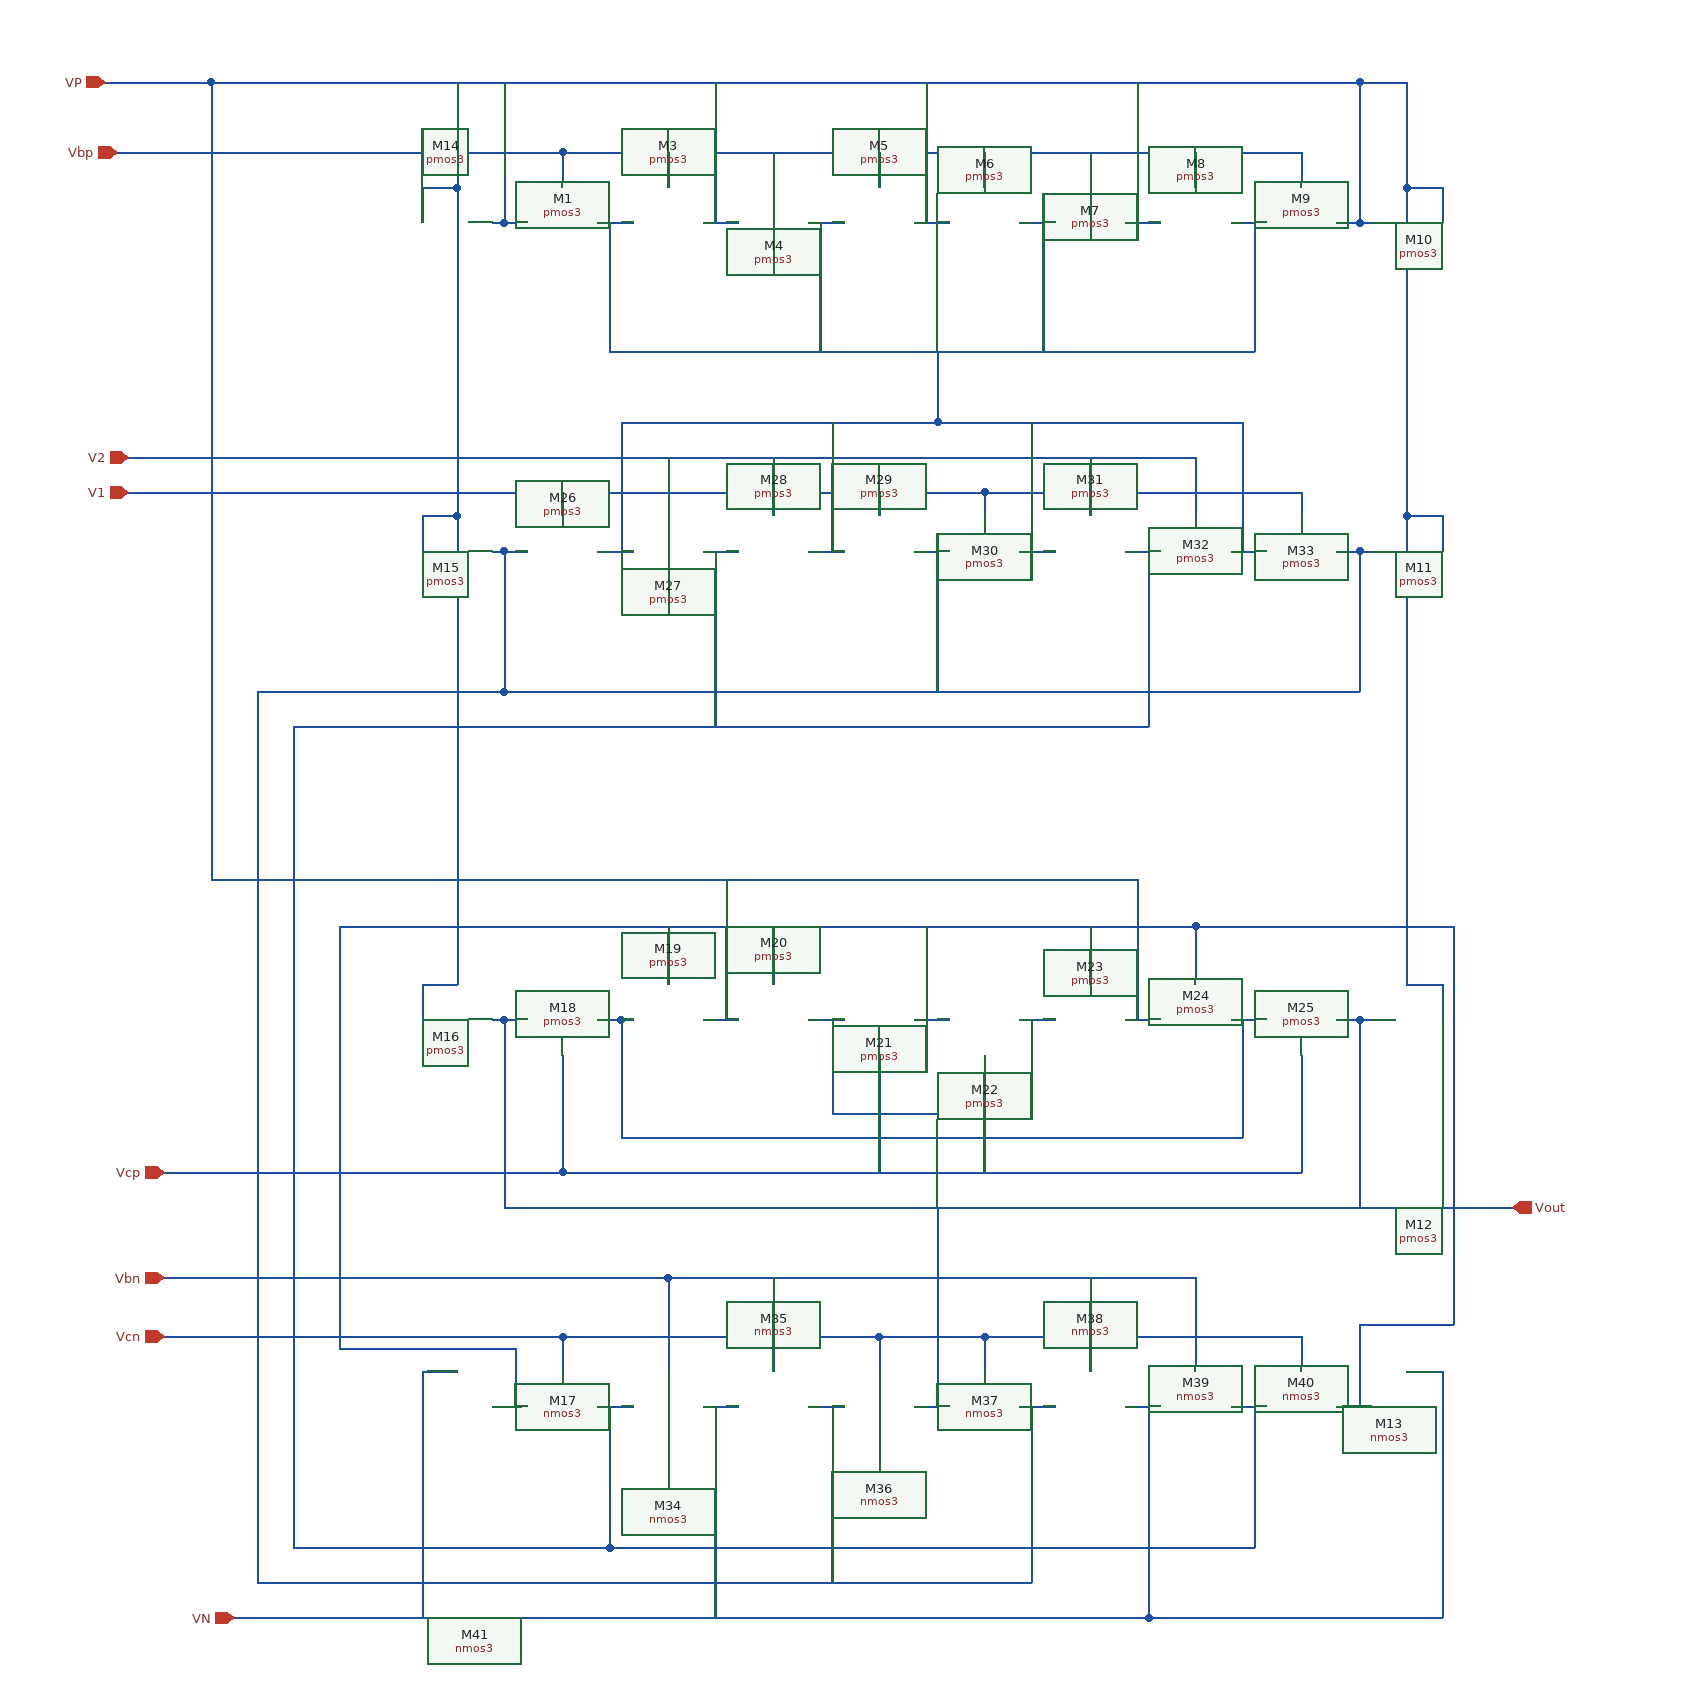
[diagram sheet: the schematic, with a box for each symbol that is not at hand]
v {xschem version=2.9.9 file_version=1.2 }
G {}
K {}
V {}
S {}
E {}
N 510 -1360 510 -1330 { lab=Vbp}
N 510 -1360 1140 -1360 { lab=Vbp}
N 1140 -1360 1140 -1330 { lab=Vbp}
N 1050 -1360 1050 -1330 { lab=Vbp}
N 960 -1360 960 -1330 { lab=Vbp}
N 870 -1360 870 -1330 { lab=Vbp}
N 780 -1360 780 -1330 { lab=Vbp}
N 690 -1360 690 -1330 { lab=Vbp}
N 600 -1360 600 -1330 { lab=Vbp}
N 540 -1300 570 -1300 { lab=#net1}
N 630 -1300 660 -1300 { lab=VP}
N 720 -1300 750 -1300 { lab=#net1}
N 810 -1300 840 -1300 { lab=VP}
N 900 -1300 930 -1300 { lab=#net1}
N 990 -1300 1020 -1300 { lab=VP}
N 1080 -1300 1110 -1300 { lab=#net1}
N 460 -1420 460 -1300 { lab=VP}
N 450 -1420 1190 -1420 { lab=VP}
N 1190 -1420 1190 -1300 { lab=VP}
N 1170 -1300 1190 -1300 { lab=VP}
N 820 -1420 820 -1300 { lab=VP}
N 1000 -1420 1000 -1300 { lab=VP}
N 640 -1420 640 -1300 { lab=VP}
N 350 -1420 450 -1420 { lab=VP}
N 350 -1360 510 -1360 { lab=Vbp}
N 550 -1300 550 -1190 { lab=#net1}
N 550 -1190 1100 -1190 { lab=#net1}
N 1100 -1300 1100 -1190 { lab=#net1}
N 920 -1300 920 -1190 { lab=#net1}
N 730 -1300 730 -1190 { lab=#net1}
N 810 -1020 840 -1020 { lab=#net2}
N 540 -1020 570 -1020 { lab=#net1}
N 630 -1020 660 -1020 { lab=#net3}
N 730 -1020 750 -1020 { lab=#net1}
N 720 -1020 730 -1020 { lab=#net1}
N 900 -1020 930 -1020 { lab=#net1}
N 990 -1020 1020 -1020 { lab=#net3}
N 1080 -1020 1110 -1020 { lab=#net1}
N 780 -1070 780 -1050 { lab=V1}
N 870 -1070 870 -1050 { lab=V1}
N 1140 -1070 1140 -1060 { lab=V1}
N 1140 -1060 1140 -1050 { lab=V1}
N 500 -1070 870 -1070 { lab=V1}
N 510 -1070 510 -1050 { lab=V1}
N 330 -1070 500 -1070 { lab=V1}
N 1050 -1100 1050 -1050 { lab=V2}
N 870 -1070 1140 -1070 { lab=V1}
N 960 -1100 960 -1050 { lab=V2}
N 690 -1090 690 -1050 { lab=V2}
N 600 -1090 600 -1050 { lab=V2}
N 600 -1100 600 -1090 { lab=V2}
N 690 -1100 690 -1090 { lab=V2}
N 330 -1100 1050 -1100 { lab=V2}
N 830 -1190 830 -1150 { lab=#net1}
N 830 -1150 830 -1130 { lab=#net1}
N 560 -1130 830 -1130 { lab=#net1}
N 560 -1130 560 -1020 { lab=#net1}
N 830 -1130 1080 -1130 { lab=#net1}
N 1080 -1130 1090 -1130 { lab=#net1}
N 1090 -1130 1090 -1020 { lab=#net1}
N 740 -1130 740 -1020 { lab=#net1}
N 910 -1130 910 -1020 { lab=#net1}
N 460 -1020 480 -1020 { lab=#net2}
N 460 -1020 460 -900 { lab=#net2}
N 1170 -1020 1190 -1020 { lab=#net2}
N 1190 -1020 1190 -900 { lab=#net2}
N 460 -900 1190 -900 { lab=#net2}
N 830 -1020 830 -900 { lab=#net2}
N 640 -1020 640 -870 { lab=#net3}
N 1010 -1020 1010 -870 { lab=#net3}
N 410 -870 1010 -870 { lab=#net3}
N 380 -900 460 -900 { lab=#net2}
N 810 -620 840 -620 { lab=#net4}
N 720 -620 750 -620 { lab=#net5}
N 900 -620 930 -620 { lab=#net5}
N 990 -620 1020 -620 { lab=VP}
N 630 -620 660 -620 { lab=VP}
N 1080 -620 1110 -620 { lab=#net6}
N 540 -620 560 -620 { lab=#net6}
N 560 -620 570 -620 { lab=#net6}
N 1270 -670 1270 -360 { lab=#net4}
N 210 -740 830 -740 { lab=VP}
N 1050 -490 1140 -490 { lab=Vcp}
N 600 -490 1050 -490 { lab=Vcp}
N 510 -490 600 -490 { lab=Vcp}
N 1270 -700 1270 -670 { lab=#net4}
N 1190 -620 1190 -510 { lab=Vout}
N 1200 -460 1320 -460 { lab=Vout}
N 210 -490 510 -490 { lab=Vcp}
N 600 -400 600 -320 { lab=Vcn}
N 690 -400 690 -320 { lab=Vcn}
N 600 -400 1040 -400 { lab=Vcn}
N 1040 -400 1050 -400 { lab=Vcn}
N 1050 -400 1050 -320 { lab=Vcn}
N 960 -400 960 -320 { lab=Vcn}
N 210 -400 600 -400 { lab=Vcn}
N 540 -290 570 -290 { lab=#net3}
N 630 -290 660 -290 { lab=VN}
N 720 -290 750 -290 { lab=#net2}
N 810 -290 840 -290 { lab=Vout}
N 900 -290 930 -290 { lab=#net2}
N 990 -290 1020 -290 { lab=VN}
N 1080 -290 1110 -290 { lab=#net3}
N 510 -350 510 -320 { lab=Vcn}
N 510 -350 780 -350 { lab=Vcn}
N 780 -350 780 -320 { lab=Vcn}
N 780 -350 870 -350 { lab=Vcn}
N 870 -350 870 -320 { lab=Vcn}
N 870 -350 1140 -350 { lab=Vcn}
N 1140 -350 1140 -320 { lab=Vcn}
N 210 -350 510 -350 { lab=Vcn}
N 380 -140 820 -140 { lab=#net2}
N 740 -290 740 -140 { lab=#net2}
N 910 -290 910 -140 { lab=#net2}
N 820 -140 910 -140 { lab=#net2}
N 410 -170 550 -170 { lab=#net3}
N 550 -290 550 -170 { lab=#net3}
N 550 -170 1100 -170 { lab=#net3}
N 1100 -290 1100 -170 { lab=#net3}
N 330 -140 380 -140 { lab=#net2}
N 360 -170 410 -170 { lab=#net3}
N 330 -900 380 -900 { lab=#net2}
N 360 -870 410 -870 { lab=#net3}
N 1010 -290 1010 -110 { lab=VN}
N 230 -110 1010 -110 { lab=VN}
N 640 -290 640 -110 { lab=VN}
N 740 -620 740 -550 { lab=#net5}
N 740 -540 910 -540 { lab=#net5}
N 910 -620 910 -550 { lab=#net5}
N 1190 -510 1190 -460 { lab=Vout}
N 830 -460 830 -290 { lab=Vout}
N 560 -620 560 -520 { lab=#net6}
N 560 -520 1090 -520 { lab=#net6}
N 1090 -620 1090 -520 { lab=#net6}
N 740 -550 740 -540 { lab=#net5}
N 910 -550 910 -540 { lab=#net5}
N 510 -590 510 -490 { lab=Vcp}
N 1140 -590 1140 -490 { lab=Vcp}
N 600 -700 600 -650 { lab=#net4}
N 690 -700 690 -650 { lab=#net4}
N 960 -700 960 -650 { lab=#net4}
N 1050 -700 1050 -650 { lab=#net4}
N 780 -590 780 -490 { lab=Vcp}
N 870 -590 870 -490 { lab=Vcp}
N 650 -740 650 -620 { lab=VP}
N 400 -700 1050 -700 { lab=#net4}
N 830 -740 990 -740 { lab=VP}
N 990 -740 1000 -740 { lab=VP}
N 1000 -740 1000 -620 { lab=VP}
N 820 -700 820 -620 { lab=#net4}
N 1050 -700 1270 -700 { lab=#net4}
N 1190 -1300 1200 -1300 { lab=VP}
N 1260 -1330 1260 -1300 { lab=VP}
N 1230 -1330 1260 -1330 { lab=VP}
N 1230 -1420 1230 -1330 { lab=VP}
N 1190 -1420 1230 -1420 { lab=VP}
N 1190 -1020 1200 -1020 { lab=#net2}
N 1260 -1050 1260 -1020 { lab=VP}
N 1230 -1050 1260 -1050 { lab=VP}
N 1230 -1330 1230 -1050 { lab=VP}
N 1170 -620 1190 -620 { lab=Vout}
N 1260 -650 1260 -620 { lab=VP}
N 1230 -650 1260 -650 { lab=VP}
N 1190 -620 1200 -620 { lab=Vout}
N 1230 -1050 1230 -650 { lab=VP}
N 1170 -290 1200 -290 { lab=#net4}
N 1190 -360 1190 -290 { lab=#net4}
N 1190 -360 1270 -360 { lab=#net4}
N 1230 -320 1260 -320 { lab=VN}
N 1260 -320 1260 -290 { lab=VN}
N 1260 -290 1260 -110 { lab=VN}
N 1010 -110 1260 -110 { lab=VN}
N 210 -1420 210 -740 { lab=VP}
N 210 -1420 350 -1420 { lab=VP}
N 120 -1420 210 -1420 { lab=VP}
N 460 -1300 480 -1300 { lab=VP}
N 450 -1300 460 -1300 { lab=VP}
N 390 -1330 420 -1330 { lab=VP}
N 390 -1330 390 -1300 { lab=VP}
N 420 -1420 420 -1330 { lab=VP}
N 450 -1020 460 -1020 { lab=#net2}
N 390 -1050 390 -1020 { lab=VP}
N 390 -1050 420 -1050 { lab=VP}
N 420 -1330 420 -1050 { lab=VP}
N 250 -140 330 -140 { lab=#net2}
N 250 -900 250 -140 { lab=#net2}
N 250 -900 330 -900 { lab=#net2}
N 280 -870 360 -870 { lab=#net3}
N 280 -870 280 -170 { lab=#net3}
N 280 -170 360 -170 { lab=#net3}
N 320 -700 400 -700 { lab=#net4}
N 460 -620 480 -620 { lab=Vout}
N 460 -620 460 -460 { lab=Vout}
N 460 -460 1200 -460 { lab=Vout}
N 450 -620 460 -620 { lab=Vout}
N 390 -650 420 -650 { lab=VP}
N 390 -650 390 -620 { lab=VP}
N 420 -1050 420 -650 { lab=VP}
N 450 -290 480 -290 { lab=#net4}
N 470 -340 470 -290 { lab=#net4}
N 320 -340 470 -340 { lab=#net4}
N 320 -700 320 -340 { lab=#net4}
N 390 -320 390 -290 { lab=VN}
N 390 -320 420 -320 { lab=VN}
N 390 -290 390 -110 { lab=VN}
N 130 -1360 350 -1360 { lab=Vbp}
N 140 -1100 330 -1100 { lab=V2}
N 140 -1070 330 -1070 { lab=V1}
N 170 -490 210 -490 { lab=Vcp}
N 170 -400 210 -400 { lab=Vcn}
N 180 -350 210 -350 { lab=Vcn}
N 170 -350 180 -350 { lab=Vcn}
C {madvlsi/pmos3.sym} 510 -1300 1 0 {name=M1
L=0.5
W=12
body=VDD
nf=1
mult=1
ad="'int((nf+1)/2) * W/nf * 0.29'" 
pd="'2*int((nf+1)/2) * (W/nf + 0.29)'"
as="'int((nf+2)/2) * W/nf * 0.29'" 
ps="'2*int((nf+2)/2) * (W/nf + 0.29)'"
nrd="'0.29 / W'" nrs="'0.29 / W'"
sa=0 sb=0 sd=0
model=pfet_01v8
spiceprefix=X
}
C {madvlsi/pmos3.sym} 600 -1300 1 0 {name=M3
L=0.5
W=12
body=VDD
nf=1
mult=1
ad="'int((nf+1)/2) * W/nf * 0.29'" 
pd="'2*int((nf+1)/2) * (W/nf + 0.29)'"
as="'int((nf+2)/2) * W/nf * 0.29'" 
ps="'2*int((nf+2)/2) * (W/nf + 0.29)'"
nrd="'0.29 / W'" nrs="'0.29 / W'"
sa=0 sb=0 sd=0
model=pfet_01v8
spiceprefix=X
}
C {madvlsi/pmos3.sym} 690 -1300 1 0 {name=M4
L=0.5
W=12
body=VDD
nf=1
mult=1
ad="'int((nf+1)/2) * W/nf * 0.29'" 
pd="'2*int((nf+1)/2) * (W/nf + 0.29)'"
as="'int((nf+2)/2) * W/nf * 0.29'" 
ps="'2*int((nf+2)/2) * (W/nf + 0.29)'"
nrd="'0.29 / W'" nrs="'0.29 / W'"
sa=0 sb=0 sd=0
model=pfet_01v8
spiceprefix=X
}
C {madvlsi/pmos3.sym} 780 -1300 1 0 {name=M5
L=0.5
W=12
body=VDD
nf=1
mult=1
ad="'int((nf+1)/2) * W/nf * 0.29'" 
pd="'2*int((nf+1)/2) * (W/nf + 0.29)'"
as="'int((nf+2)/2) * W/nf * 0.29'" 
ps="'2*int((nf+2)/2) * (W/nf + 0.29)'"
nrd="'0.29 / W'" nrs="'0.29 / W'"
sa=0 sb=0 sd=0
model=pfet_01v8
spiceprefix=X
}
C {madvlsi/pmos3.sym} 870 -1300 1 0 {name=M6
L=0.5
W=12
body=VDD
nf=1
mult=1
ad="'int((nf+1)/2) * W/nf * 0.29'" 
pd="'2*int((nf+1)/2) * (W/nf + 0.29)'"
as="'int((nf+2)/2) * W/nf * 0.29'" 
ps="'2*int((nf+2)/2) * (W/nf + 0.29)'"
nrd="'0.29 / W'" nrs="'0.29 / W'"
sa=0 sb=0 sd=0
model=pfet_01v8
spiceprefix=X
}
C {madvlsi/pmos3.sym} 960 -1300 1 0 {name=M7
L=0.5
W=12
body=VDD
nf=1
mult=1
ad="'int((nf+1)/2) * W/nf * 0.29'" 
pd="'2*int((nf+1)/2) * (W/nf + 0.29)'"
as="'int((nf+2)/2) * W/nf * 0.29'" 
ps="'2*int((nf+2)/2) * (W/nf + 0.29)'"
nrd="'0.29 / W'" nrs="'0.29 / W'"
sa=0 sb=0 sd=0
model=pfet_01v8
spiceprefix=X
}
C {madvlsi/pmos3.sym} 1050 -1300 1 0 {name=M8
L=0.5
W=12
body=VDD
nf=1
mult=1
ad="'int((nf+1)/2) * W/nf * 0.29'" 
pd="'2*int((nf+1)/2) * (W/nf + 0.29)'"
as="'int((nf+2)/2) * W/nf * 0.29'" 
ps="'2*int((nf+2)/2) * (W/nf + 0.29)'"
nrd="'0.29 / W'" nrs="'0.29 / W'"
sa=0 sb=0 sd=0
model=pfet_01v8
spiceprefix=X
}
C {madvlsi/pmos3.sym} 1140 -1300 1 0 {name=M9
L=0.5
W=12
body=VDD
nf=1
mult=1
ad="'int((nf+1)/2) * W/nf * 0.29'" 
pd="'2*int((nf+1)/2) * (W/nf + 0.29)'"
as="'int((nf+2)/2) * W/nf * 0.29'" 
ps="'2*int((nf+2)/2) * (W/nf + 0.29)'"
nrd="'0.29 / W'" nrs="'0.29 / W'"
sa=0 sb=0 sd=0
model=pfet_01v8
spiceprefix=X
}
C {madvlsi/pmos3.sym} 510 -620 3 0 {name=M18
L=0.5
W=12
body=VDD
nf=1
mult=1
ad="'int((nf+1)/2) * W/nf * 0.29'" 
pd="'2*int((nf+1)/2) * (W/nf + 0.29)'"
as="'int((nf+2)/2) * W/nf * 0.29'" 
ps="'2*int((nf+2)/2) * (W/nf + 0.29)'"
nrd="'0.29 / W'" nrs="'0.29 / W'"
sa=0 sb=0 sd=0
model=pfet_01v8
spiceprefix=X
}
C {madvlsi/pmos3.sym} 600 -620 1 0 {name=M19
L=0.5
W=12
body=VDD
nf=1
mult=1
ad="'int((nf+1)/2) * W/nf * 0.29'" 
pd="'2*int((nf+1)/2) * (W/nf + 0.29)'"
as="'int((nf+2)/2) * W/nf * 0.29'" 
ps="'2*int((nf+2)/2) * (W/nf + 0.29)'"
nrd="'0.29 / W'" nrs="'0.29 / W'"
sa=0 sb=0 sd=0
model=pfet_01v8
spiceprefix=X
}
C {madvlsi/pmos3.sym} 690 -620 1 0 {name=M20
L=0.5
W=12
body=VDD
nf=1
mult=1
ad="'int((nf+1)/2) * W/nf * 0.29'" 
pd="'2*int((nf+1)/2) * (W/nf + 0.29)'"
as="'int((nf+2)/2) * W/nf * 0.29'" 
ps="'2*int((nf+2)/2) * (W/nf + 0.29)'"
nrd="'0.29 / W'" nrs="'0.29 / W'"
sa=0 sb=0 sd=0
model=pfet_01v8
spiceprefix=X
}
C {madvlsi/pmos3.sym} 780 -620 3 0 {name=M21
L=0.5
W=12
body=VDD
nf=1
mult=1
ad="'int((nf+1)/2) * W/nf * 0.29'" 
pd="'2*int((nf+1)/2) * (W/nf + 0.29)'"
as="'int((nf+2)/2) * W/nf * 0.29'" 
ps="'2*int((nf+2)/2) * (W/nf + 0.29)'"
nrd="'0.29 / W'" nrs="'0.29 / W'"
sa=0 sb=0 sd=0
model=pfet_01v8
spiceprefix=X
}
C {madvlsi/pmos3.sym} 870 -620 3 0 {name=M22
L=0.5
W=12
body=VDD
nf=1
mult=1
ad="'int((nf+1)/2) * W/nf * 0.29'" 
pd="'2*int((nf+1)/2) * (W/nf + 0.29)'"
as="'int((nf+2)/2) * W/nf * 0.29'" 
ps="'2*int((nf+2)/2) * (W/nf + 0.29)'"
nrd="'0.29 / W'" nrs="'0.29 / W'"
sa=0 sb=0 sd=0
model=pfet_01v8
spiceprefix=X
}
C {madvlsi/pmos3.sym} 960 -620 1 0 {name=M23
L=0.5
W=12
body=VDD
nf=1
mult=1
ad="'int((nf+1)/2) * W/nf * 0.29'" 
pd="'2*int((nf+1)/2) * (W/nf + 0.29)'"
as="'int((nf+2)/2) * W/nf * 0.29'" 
ps="'2*int((nf+2)/2) * (W/nf + 0.29)'"
nrd="'0.29 / W'" nrs="'0.29 / W'"
sa=0 sb=0 sd=0
model=pfet_01v8
spiceprefix=X
}
C {madvlsi/pmos3.sym} 1050 -620 1 0 {name=M24
L=0.5
W=12
body=VDD
nf=1
mult=1
ad="'int((nf+1)/2) * W/nf * 0.29'" 
pd="'2*int((nf+1)/2) * (W/nf + 0.29)'"
as="'int((nf+2)/2) * W/nf * 0.29'" 
ps="'2*int((nf+2)/2) * (W/nf + 0.29)'"
nrd="'0.29 / W'" nrs="'0.29 / W'"
sa=0 sb=0 sd=0
model=pfet_01v8
spiceprefix=X
}
C {madvlsi/pmos3.sym} 1140 -620 3 0 {name=M25
L=0.5
W=12
body=VDD
nf=1
mult=1
ad="'int((nf+1)/2) * W/nf * 0.29'" 
pd="'2*int((nf+1)/2) * (W/nf + 0.29)'"
as="'int((nf+2)/2) * W/nf * 0.29'" 
ps="'2*int((nf+2)/2) * (W/nf + 0.29)'"
nrd="'0.29 / W'" nrs="'0.29 / W'"
sa=0 sb=0 sd=0
model=pfet_01v8
spiceprefix=X
}
C {madvlsi/pmos3.sym} 510 -1020 1 0 {name=M26
L=0.5
W=12
body=VDD
nf=1
mult=1
ad="'int((nf+1)/2) * W/nf * 0.29'" 
pd="'2*int((nf+1)/2) * (W/nf + 0.29)'"
as="'int((nf+2)/2) * W/nf * 0.29'" 
ps="'2*int((nf+2)/2) * (W/nf + 0.29)'"
nrd="'0.29 / W'" nrs="'0.29 / W'"
sa=0 sb=0 sd=0
model=pfet_01v8
spiceprefix=X
}
C {madvlsi/pmos3.sym} 600 -1020 1 0 {name=M27
L=0.5
W=12
body=VDD
nf=1
mult=1
ad="'int((nf+1)/2) * W/nf * 0.29'" 
pd="'2*int((nf+1)/2) * (W/nf + 0.29)'"
as="'int((nf+2)/2) * W/nf * 0.29'" 
ps="'2*int((nf+2)/2) * (W/nf + 0.29)'"
nrd="'0.29 / W'" nrs="'0.29 / W'"
sa=0 sb=0 sd=0
model=pfet_01v8
spiceprefix=X
}
C {madvlsi/pmos3.sym} 690 -1020 1 0 {name=M28
L=0.5
W=12
body=VDD
nf=1
mult=1
ad="'int((nf+1)/2) * W/nf * 0.29'" 
pd="'2*int((nf+1)/2) * (W/nf + 0.29)'"
as="'int((nf+2)/2) * W/nf * 0.29'" 
ps="'2*int((nf+2)/2) * (W/nf + 0.29)'"
nrd="'0.29 / W'" nrs="'0.29 / W'"
sa=0 sb=0 sd=0
model=pfet_01v8
spiceprefix=X
}
C {madvlsi/pmos3.sym} 780 -1020 1 0 {name=M29
L=0.5
W=12
body=VDD
nf=1
mult=1
ad="'int((nf+1)/2) * W/nf * 0.29'" 
pd="'2*int((nf+1)/2) * (W/nf + 0.29)'"
as="'int((nf+2)/2) * W/nf * 0.29'" 
ps="'2*int((nf+2)/2) * (W/nf + 0.29)'"
nrd="'0.29 / W'" nrs="'0.29 / W'"
sa=0 sb=0 sd=0
model=pfet_01v8
spiceprefix=X
}
C {madvlsi/pmos3.sym} 870 -1020 1 0 {name=M30
L=0.5
W=12
body=VDD
nf=1
mult=1
ad="'int((nf+1)/2) * W/nf * 0.29'" 
pd="'2*int((nf+1)/2) * (W/nf + 0.29)'"
as="'int((nf+2)/2) * W/nf * 0.29'" 
ps="'2*int((nf+2)/2) * (W/nf + 0.29)'"
nrd="'0.29 / W'" nrs="'0.29 / W'"
sa=0 sb=0 sd=0
model=pfet_01v8
spiceprefix=X
}
C {madvlsi/pmos3.sym} 960 -1020 1 0 {name=M31
L=0.5
W=12
body=VDD
nf=1
mult=1
ad="'int((nf+1)/2) * W/nf * 0.29'" 
pd="'2*int((nf+1)/2) * (W/nf + 0.29)'"
as="'int((nf+2)/2) * W/nf * 0.29'" 
ps="'2*int((nf+2)/2) * (W/nf + 0.29)'"
nrd="'0.29 / W'" nrs="'0.29 / W'"
sa=0 sb=0 sd=0
model=pfet_01v8
spiceprefix=X
}
C {madvlsi/pmos3.sym} 1050 -1020 1 0 {name=M32
L=0.5
W=12
body=VDD
nf=1
mult=1
ad="'int((nf+1)/2) * W/nf * 0.29'" 
pd="'2*int((nf+1)/2) * (W/nf + 0.29)'"
as="'int((nf+2)/2) * W/nf * 0.29'" 
ps="'2*int((nf+2)/2) * (W/nf + 0.29)'"
nrd="'0.29 / W'" nrs="'0.29 / W'"
sa=0 sb=0 sd=0
model=pfet_01v8
spiceprefix=X
}
C {madvlsi/pmos3.sym} 1140 -1020 1 0 {name=M33
L=0.5
W=12
body=VDD
nf=1
mult=1
ad="'int((nf+1)/2) * W/nf * 0.29'" 
pd="'2*int((nf+1)/2) * (W/nf + 0.29)'"
as="'int((nf+2)/2) * W/nf * 0.29'" 
ps="'2*int((nf+2)/2) * (W/nf + 0.29)'"
nrd="'0.29 / W'" nrs="'0.29 / W'"
sa=0 sb=0 sd=0
model=pfet_01v8
spiceprefix=X
}
C {madvlsi/nmos3.sym} 600 -290 1 0 {name=M34
L=0.5
W=12
body=GND
nf=1
mult=1
ad="'int((nf+1)/2) * W/nf * 0.29'" 
pd="'2*int((nf+1)/2) * (W/nf + 0.29)'"
as="'int((nf+2)/2) * W/nf * 0.29'" 
ps="'2*int((nf+2)/2) * (W/nf + 0.29)'"
nrd="'0.29 / W'" nrs="'0.29 / W'"
sa=0 sb=0 sd=0
model=nfet_01v8
spiceprefix=X
}
C {madvlsi/nmos3.sym} 690 -290 1 0 {name=M35
L=0.5
W=12
body=GND
nf=1
mult=1
ad="'int((nf+1)/2) * W/nf * 0.29'" 
pd="'2*int((nf+1)/2) * (W/nf + 0.29)'"
as="'int((nf+2)/2) * W/nf * 0.29'" 
ps="'2*int((nf+2)/2) * (W/nf + 0.29)'"
nrd="'0.29 / W'" nrs="'0.29 / W'"
sa=0 sb=0 sd=0
model=nfet_01v8
spiceprefix=X
}
C {madvlsi/nmos3.sym} 780 -290 1 0 {name=M36
L=0.5
W=12
body=GND
nf=1
mult=1
ad="'int((nf+1)/2) * W/nf * 0.29'" 
pd="'2*int((nf+1)/2) * (W/nf + 0.29)'"
as="'int((nf+2)/2) * W/nf * 0.29'" 
ps="'2*int((nf+2)/2) * (W/nf + 0.29)'"
nrd="'0.29 / W'" nrs="'0.29 / W'"
sa=0 sb=0 sd=0
model=nfet_01v8
spiceprefix=X
}
C {madvlsi/nmos3.sym} 870 -290 1 0 {name=M37
L=0.5
W=12
body=GND
nf=1
mult=1
ad="'int((nf+1)/2) * W/nf * 0.29'" 
pd="'2*int((nf+1)/2) * (W/nf + 0.29)'"
as="'int((nf+2)/2) * W/nf * 0.29'" 
ps="'2*int((nf+2)/2) * (W/nf + 0.29)'"
nrd="'0.29 / W'" nrs="'0.29 / W'"
sa=0 sb=0 sd=0
model=nfet_01v8
spiceprefix=X
}
C {madvlsi/nmos3.sym} 960 -290 1 0 {name=M38
L=0.5
W=12
body=GND
nf=1
mult=1
ad="'int((nf+1)/2) * W/nf * 0.29'" 
pd="'2*int((nf+1)/2) * (W/nf + 0.29)'"
as="'int((nf+2)/2) * W/nf * 0.29'" 
ps="'2*int((nf+2)/2) * (W/nf + 0.29)'"
nrd="'0.29 / W'" nrs="'0.29 / W'"
sa=0 sb=0 sd=0
model=nfet_01v8
spiceprefix=X
}
C {madvlsi/nmos3.sym} 1050 -290 1 0 {name=M39
L=0.5
W=12
body=GND
nf=1
mult=1
ad="'int((nf+1)/2) * W/nf * 0.29'" 
pd="'2*int((nf+1)/2) * (W/nf + 0.29)'"
as="'int((nf+2)/2) * W/nf * 0.29'" 
ps="'2*int((nf+2)/2) * (W/nf + 0.29)'"
nrd="'0.29 / W'" nrs="'0.29 / W'"
sa=0 sb=0 sd=0
model=nfet_01v8
spiceprefix=X
}
C {madvlsi/nmos3.sym} 1140 -290 1 0 {name=M40
L=0.5
W=12
body=GND
nf=1
mult=1
ad="'int((nf+1)/2) * W/nf * 0.29'" 
pd="'2*int((nf+1)/2) * (W/nf + 0.29)'"
as="'int((nf+2)/2) * W/nf * 0.29'" 
ps="'2*int((nf+2)/2) * (W/nf + 0.29)'"
nrd="'0.29 / W'" nrs="'0.29 / W'"
sa=0 sb=0 sd=0
model=nfet_01v8
spiceprefix=X
}
C {madvlsi/pmos3.sym} 1230 -1300 1 0 {name=M10
L=0.5
W=12
body=VDD
nf=1
mult=1
ad="'int((nf+1)/2) * W/nf * 0.29'" 
pd="'2*int((nf+1)/2) * (W/nf + 0.29)'"
as="'int((nf+2)/2) * W/nf * 0.29'" 
ps="'2*int((nf+2)/2) * (W/nf + 0.29)'"
nrd="'0.29 / W'" nrs="'0.29 / W'"
sa=0 sb=0 sd=0
model=pfet_01v8
spiceprefix=X
}
C {madvlsi/pmos3.sym} 1230 -1020 1 0 {name=M11
L=0.5
W=12
body=VDD
nf=1
mult=1
ad="'int((nf+1)/2) * W/nf * 0.29'" 
pd="'2*int((nf+1)/2) * (W/nf + 0.29)'"
as="'int((nf+2)/2) * W/nf * 0.29'" 
ps="'2*int((nf+2)/2) * (W/nf + 0.29)'"
nrd="'0.29 / W'" nrs="'0.29 / W'"
sa=0 sb=0 sd=0
model=pfet_01v8
spiceprefix=X
}
C {madvlsi/pmos3.sym} 1230 -620 1 0 {name=M12
L=0.5
W=12
body=VDD
nf=1
mult=1
ad="'int((nf+1)/2) * W/nf * 0.29'" 
pd="'2*int((nf+1)/2) * (W/nf + 0.29)'"
as="'int((nf+2)/2) * W/nf * 0.29'" 
ps="'2*int((nf+2)/2) * (W/nf + 0.29)'"
nrd="'0.29 / W'" nrs="'0.29 / W'"
sa=0 sb=0 sd=0
model=pfet_01v8
spiceprefix=X
}
C {madvlsi/nmos3.sym} 1230 -290 1 0 {name=M13
L=0.5
W=12
body=GND
nf=1
mult=1
ad="'int((nf+1)/2) * W/nf * 0.29'" 
pd="'2*int((nf+1)/2) * (W/nf + 0.29)'"
as="'int((nf+2)/2) * W/nf * 0.29'" 
ps="'2*int((nf+2)/2) * (W/nf + 0.29)'"
nrd="'0.29 / W'" nrs="'0.29 / W'"
sa=0 sb=0 sd=0
model=nfet_01v8
spiceprefix=X
}
C {madvlsi/pmos3.sym} 420 -1300 1 0 {name=M14
L=0.5
W=12
body=VDD
nf=1
mult=1
ad="'int((nf+1)/2) * W/nf * 0.29'" 
pd="'2*int((nf+1)/2) * (W/nf + 0.29)'"
as="'int((nf+2)/2) * W/nf * 0.29'" 
ps="'2*int((nf+2)/2) * (W/nf + 0.29)'"
nrd="'0.29 / W'" nrs="'0.29 / W'"
sa=0 sb=0 sd=0
model=pfet_01v8
spiceprefix=X
}
C {madvlsi/pmos3.sym} 420 -1020 1 0 {name=M15
L=0.5
W=12
body=VDD
nf=1
mult=1
ad="'int((nf+1)/2) * W/nf * 0.29'" 
pd="'2*int((nf+1)/2) * (W/nf + 0.29)'"
as="'int((nf+2)/2) * W/nf * 0.29'" 
ps="'2*int((nf+2)/2) * (W/nf + 0.29)'"
nrd="'0.29 / W'" nrs="'0.29 / W'"
sa=0 sb=0 sd=0
model=pfet_01v8
spiceprefix=X
}
C {madvlsi/pmos3.sym} 420 -620 1 0 {name=M16
L=0.5
W=12
body=VDD
nf=1
mult=1
ad="'int((nf+1)/2) * W/nf * 0.29'" 
pd="'2*int((nf+1)/2) * (W/nf + 0.29)'"
as="'int((nf+2)/2) * W/nf * 0.29'" 
ps="'2*int((nf+2)/2) * (W/nf + 0.29)'"
nrd="'0.29 / W'" nrs="'0.29 / W'"
sa=0 sb=0 sd=0
model=pfet_01v8
spiceprefix=X
}
C {madvlsi/nmos3.sym} 510 -290 1 0 {name=M17
L=0.5
W=12
body=GND
nf=1
mult=1
ad="'int((nf+1)/2) * W/nf * 0.29'" 
pd="'2*int((nf+1)/2) * (W/nf + 0.29)'"
as="'int((nf+2)/2) * W/nf * 0.29'" 
ps="'2*int((nf+2)/2) * (W/nf + 0.29)'"
nrd="'0.29 / W'" nrs="'0.29 / W'"
sa=0 sb=0 sd=0
model=nfet_01v8
spiceprefix=X
}
C {madvlsi/nmos3.sym} 420 -290 1 0 {name=M41
L=0.5
W=12
body=GND
nf=1
mult=1
ad="'int((nf+1)/2) * W/nf * 0.29'" 
pd="'2*int((nf+1)/2) * (W/nf + 0.29)'"
as="'int((nf+2)/2) * W/nf * 0.29'" 
ps="'2*int((nf+2)/2) * (W/nf + 0.29)'"
nrd="'0.29 / W'" nrs="'0.29 / W'"
sa=0 sb=0 sd=0
model=nfet_01v8
spiceprefix=X
}
C {devices/iopin.sym} 120 -1420 2 0 {name=p1 lab=VP}
C {devices/iopin.sym} 230 -110 2 0 {name=p2 lab=VN}
C {devices/ipin.sym} 130 -1360 0 0 {name=p3 lab=Vbp}
C {devices/ipin.sym} 140 -1100 0 0 {name=p4 lab=V2}
C {devices/ipin.sym} 140 -1070 0 0 {name=p5 lab=V1}
C {devices/ipin.sym} 170 -490 0 0 {name=p6 lab=Vcp}
C {devices/ipin.sym} 170 -400 0 0 {name=p7 lab=Vbn}
C {devices/ipin.sym} 170 -350 0 0 {name=p8 lab=Vcn}
C {devices/opin.sym} 1320 -460 0 0 {name=p9 lab=Vout}
